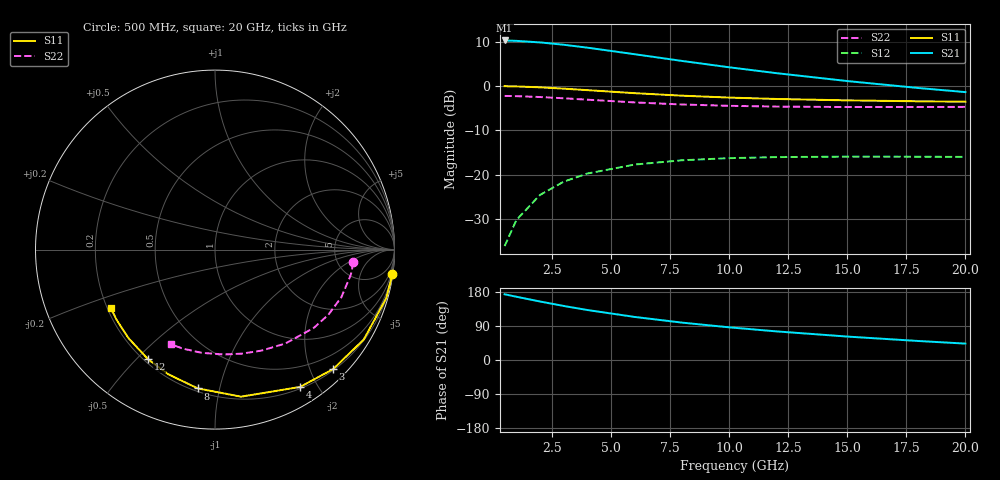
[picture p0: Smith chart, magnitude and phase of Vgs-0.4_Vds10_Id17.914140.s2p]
# Hz S RI R 50
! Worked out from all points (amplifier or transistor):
!   12 points, 500 MHz to 20 GHz, reference 50 ohm
!   highest |S21| = 10.3 dB at 500 MHz (marker M1)
!   |S21| within 3 dB of that: start of sweep to 5.852 GHz
!   unconditionally stable (mu >= 1): 16.94 GHz to end of sweep
!   at 2 GHz: K = 0.11, MSG = 17.2 dB, |S12| = -24.6 dB
!   at 8 GHz: K = 0.44, MSG = 11.2 dB, |S12| = -16.8 dB
!   at 20 GHz: K = 1.23, MAG = 4.4 dB, |S12| = -16.0 dB
!   S11 on the Smith chart (normalised r, x): 500 MHz: 0, -14; 3 GHz: 0.22, -2.38; 4 GHz: 0.22, -1.78; 8 GHz: 0.22, -0.86; 12 GHz: 0.22, -0.54; 20 GHz: 0.21, -0.25
5e8  0.9882 -0.1385  -3.261 0.3758  0.00149 0.0154  0.771 -0.0713
1e9  0.9538 -0.2712  -3.164 0.7352  0.00582 0.0301  0.7567 -0.1404
2e9  0.8291 -0.5008  -2.812 1.351  0.0215 0.0548  0.7043 -0.2647
3e9  0.6583 -0.6657  -2.333 1.781  0.0427 0.0711  0.6312 -0.3636
4e9  0.474 -0.7651  -1.819 2.025  0.0653 0.0791  0.5497 -0.4367
6e9  0.1449 -0.8193  -0.9208 2.102  0.1044 0.0768  0.3929 -0.5228
8e9  -0.096 -0.7734  -0.2918 1.905  0.1307 0.0624  0.2596 -0.5627
1e10  -0.2609 -0.6943  0.107 1.629  0.1464 0.0451  0.1479 -0.5798
1.2e10  -0.3739 -0.6099  0.3499 1.357  0.1548 0.0283  0.0515 -0.5844
1.5e10  -0.4832 -0.492  0.5382 1.005  0.1593 0.00668  -0.0735 -0.5753
1.8e10  -0.5496 -0.3889  0.6098 0.7315  0.1588 -0.0105  -0.1803 -0.5513
2e10  -0.5792 -0.3276  0.6227 0.5861  0.157 -0.02  -0.2429 -0.5287
